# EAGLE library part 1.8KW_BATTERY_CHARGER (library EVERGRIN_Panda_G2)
1.8 kW battery charger

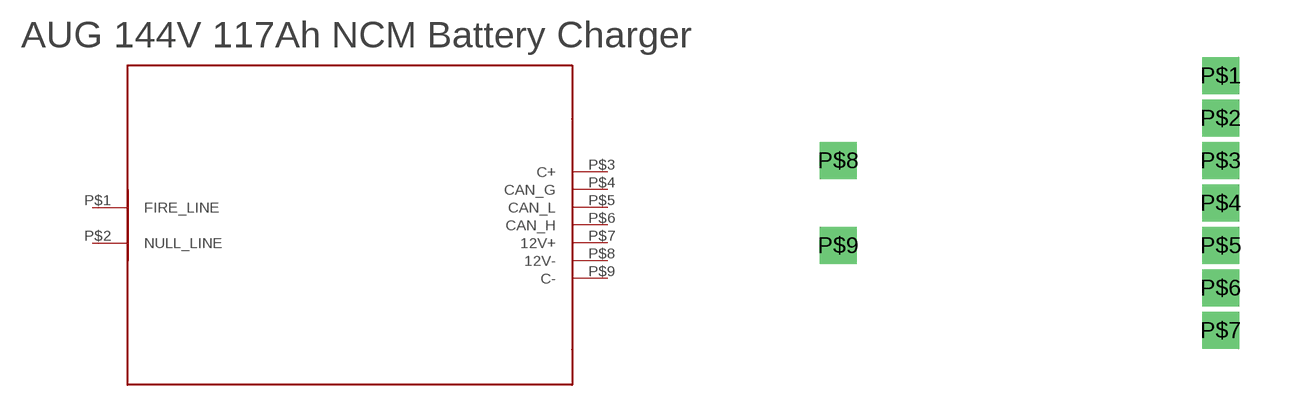
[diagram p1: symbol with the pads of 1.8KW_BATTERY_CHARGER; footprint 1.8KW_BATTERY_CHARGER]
Designator prefix -

## 1.8KW_BATTERY_CHARGER  [1.8KW_BATTERY_CHARGER]
P$1  FIRE_LINE
P$2  NULL_LINE
P$3  C+
P$4  CAN_G
P$5  CAN_L
P$6  CAN_H
P$7  12V+
P$8  12V-
P$9  C-

## Footprint 1.8KW_BATTERY_CHARGER (pad centres in mm)
drill 0.6 square: P$1 6.35,15.24; P$2 6.35,13.97; P$3 6.35,12.7; P$4 6.35,11.43; P$5 6.35,10.16; P$6 6.35,8.89; P$7 6.35,7.62; P$8 -5.08,12.7; P$9 -5.08,10.16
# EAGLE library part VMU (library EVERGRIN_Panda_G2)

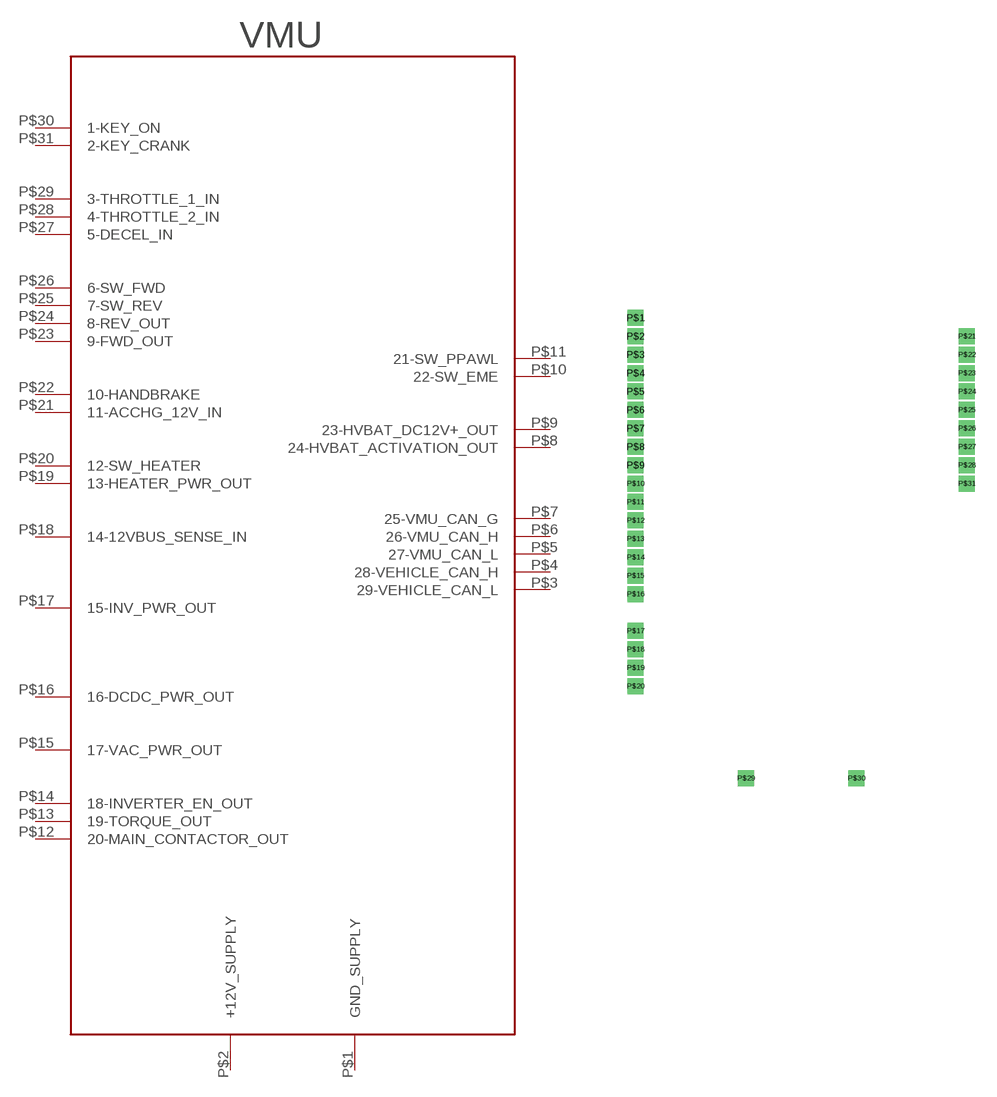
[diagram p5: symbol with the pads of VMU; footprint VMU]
Designator prefix -

## VMU  [VMU]
P$1  GND_SUPPLY
P$2  +12V_SUPPLY
P$3  29-VEHICLE_CAN_L
P$4  28-VEHICLE_CAN_H
P$5  27-VMU_CAN_L
P$6  26-VMU_CAN_H
P$7  25-VMU_CAN_G
P$8  24-HVBAT_ACTIVATION_OUT  out
P$9  23-HVBAT_DC12V+_OUT  out
P$10  22-SW_EME  in
P$11  21-SW_PPAWL
P$12  20-MAIN_CONTACTOR_OUT  in
P$13  19-TORQUE_OUT  out
P$14  18-INVERTER_EN_OUT  out
P$15  17-VAC_PWR_OUT  out
P$16  16-DCDC_PWR_OUT  out
P$17  15-INV_PWR_OUT
P$18  14-12VBUS_SENSE_IN  in
P$19  13-HEATER_PWR_OUT  out
P$20  12-SW_HEATER  in
P$21  11-ACCHG_12V_IN
P$22  10-HANDBRAKE  in
P$23  9-FWD_OUT  in
P$24  8-REV_OUT  out
P$25  7-SW_REV  in
P$26  6-SW_FWD  in
P$27  5-DECEL_IN  in
P$28  4-THROTTLE_2_IN  in
P$29  3-THROTTLE_1_IN  in
P$30  1-KEY_ON  in
P$31  2-KEY_CRANK  in

## Footprint VMU (pad centres in mm)
drill 0.6 square: P$1 0,31.75; P$2 0,30.48; P$3 0,29.21; P$4 0,27.94; P$5 0,26.67; P$6 0,25.4; P$7 0,24.13; P$8 0,22.86; P$9 0,21.59; P$10 0,20.32; P$11 0,19.05; P$12 0,17.78; P$13 0,16.51; P$14 0,15.24; P$15 0,13.97; P$16 0,12.7; P$17 0,10.16; P$18 0,8.89; P$19 0,7.62; P$20 0,6.35; P$21 22.86,30.48; P$22 22.86,29.21; P$23 22.86,27.94; P$24 22.86,26.67; P$25 22.86,25.4; P$26 22.86,24.13; P$27 22.86,22.86; P$28 22.86,21.59; P$29 7.62,0; P$30 15.24,0; P$31 22.86,20.32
